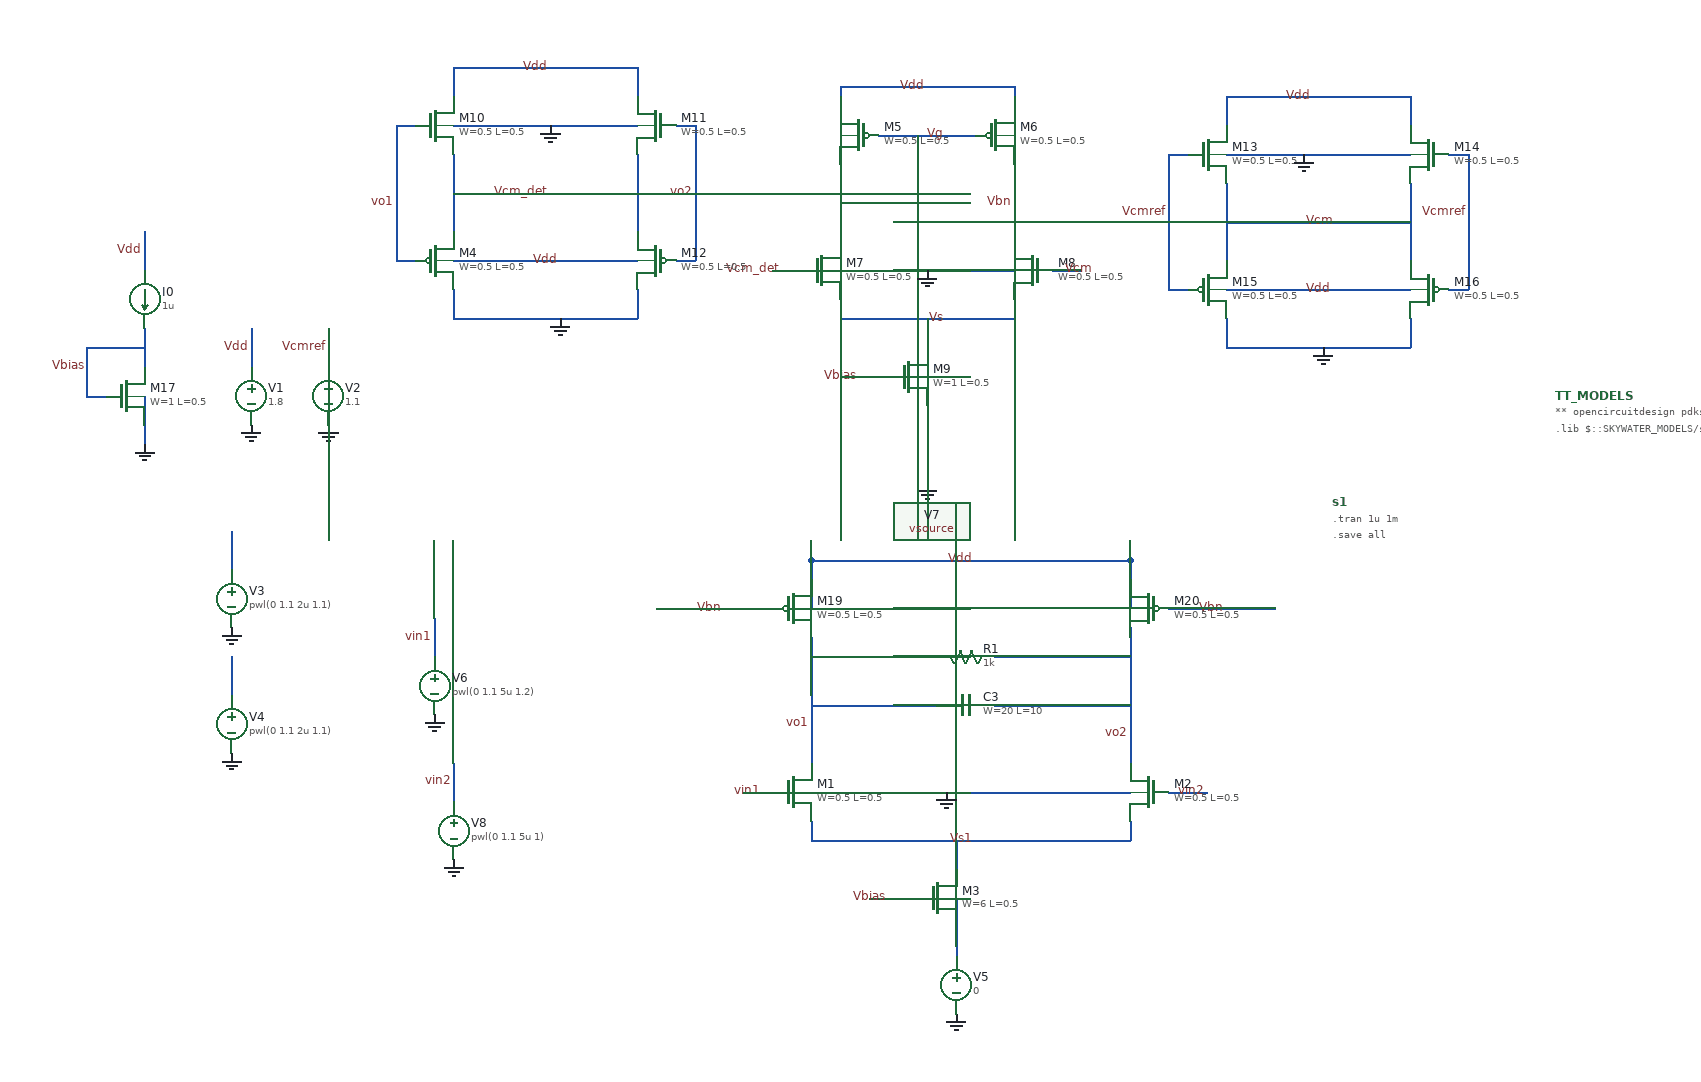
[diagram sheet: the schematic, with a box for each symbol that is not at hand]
v {xschem version=3.4.4 file_version=1.2
}
G {}
K {}
V {}
S {}
E {}
N 440 -20 440 0 {
lab=Vs1}
N 440 0 620 0 {
lab=Vs1}
N 770 -20 770 0 {
lab=Vs1}
N 440 -290 440 -270 {
lab=Vdd}
N 440 -290 620 -290 {
lab=Vdd}
N 770 -290 770 -270 {
lab=Vdd}
N 620 -290 770 -290 {
lab=Vdd}
N 620 0 770 0 {
lab=Vs1}
N 470 -700 470 -620 {
lab=Vg}
N 650 -700 650 -620 {
lab=Vbn}
N 470 -780 470 -760 {
lab=Vdd}
N 470 -780 650 -780 {
lab=Vdd}
N 650 -780 650 -760 {
lab=Vdd}
N 470 -560 470 -540 {
lab=Vs}
N 470 -540 650 -540 {
lab=Vs}
N 650 -560 650 -540 {
lab=Vs}
N 510 -730 610 -730 {
lab=Vg}
N 550 -730 550 -660 {
lab=Vg}
N 470 -660 550 -660 {
lab=Vg}
N 70 -800 70 -770 {
lab=Vdd}
N 70 -800 260 -800 {
lab=Vdd}
N 260 -800 260 -770 {
lab=Vdd}
N 70 -710 70 -630 {
lab=Vcm_det}
N 260 -710 260 -630 {
lab=Vcm_det}
N 70 -570 70 -540 {
lab=GND}
N 70 -540 260 -540 {
lab=GND}
N 260 -570 260 -540 {
lab=GND}
N 10 -740 30 -740 {
lab=vo1}
N 10 -740 10 -600 {
lab=vo1}
N 10 -600 30 -600 {
lab=vo1}
N 300 -740 320 -740 {
lab=vo2}
N 320 -740 320 -600 {
lab=vo2}
N 300 -600 320 -600 {
lab=vo2}
N 870 -770 870 -740 {
lab=Vdd}
N 870 -770 1060 -770 {
lab=Vdd}
N 1060 -770 1060 -740 {
lab=Vdd}
N 870 -680 870 -600 {
lab=Vcm}
N 1060 -680 1060 -600 {
lab=Vcm}
N 870 -540 870 -510 {
lab=GND}
N 870 -510 1060 -510 {
lab=GND}
N 1060 -540 1060 -510 {
lab=GND}
N 810 -710 830 -710 {
lab=Vcmref}
N 810 -710 810 -570 {
lab=Vcmref}
N 810 -570 830 -570 {
lab=Vcmref}
N 1100 -710 1120 -710 {
lab=Vcmref}
N 1120 -710 1120 -570 {
lab=Vcmref}
N 1100 -570 1120 -570 {
lab=Vcmref}
N 560 -540 560 -510 {
lab=Vs}
N 560 -450 560 -420 {
lab=#net1}
N 440 -140 570 -140 {
lab=vo1}
N 630 -140 770 -140 {
lab=vo2}
N -140 -530 -140 -490 {
lab=Vdd}
N 70 -670 260 -670 {
lab=Vcm_det}
N 870 -640 1060 -640 {
lab=Vcm}
N -250 -530 -250 -490 {
lab=Vbias}
N -250 -630 -250 -590 {
lab=Vdd}
N -310 -460 -290 -460 {
lab=Vbias}
N -310 -510 -310 -460 {
lab=Vbias}
N -310 -510 -250 -510 {
lab=Vbias}
N 280 -240 400 -240 {
lab=Vbn}
N 810 -240 920 -240 {
lab=Vbn}
N 400 -590 430 -590 {
lab=Vcm_det}
N 690 -590 720 -590 {
lab=Vcm}
N 370 -50 400 -50 {
lab=vin1}
N 810 -50 850 -50 {
lab=vin2}
N -60 -530 -60 -490 {
lab=Vcmref}
N 470 -480 520 -480 {
lab=Vbias}
N -160 -320 -160 -280 {
lab=#net2}
N -160 -190 -160 -150 {
lab=#net3}
N 440 -150 440 -80 {
lab=vo1}
N 770 -150 770 -80 {
lab=vo2}
N 770 -220 770 -150 {
lab=vo2}
N 70 -740 260 -740 {
lab=GND}
N 70 -600 260 -600 {
lab=Vdd}
N 470 -590 650 -590 {
lab=GND}
N 440 -210 440 -140 {
lab=vo1}
N 870 -710 1060 -710 {
lab=GND}
N 870 -570 1060 -570 {
lab=Vdd}
N 440 -290 440 -240 {
lab=Vdd}
N 770 -290 770 -240 {
lab=Vdd}
N 590 0 590 30 {
lab=Vs1}
N 590 90 590 120 {
lab=#net4}
N 500 60 550 60 {
lab=Vbias}
N 590 60 590 110 {
lab=#net4}
N 440 -50 770 -50 {
lab=GND}
N 560 -480 560 -440 {
lab=#net1}
N 470 -770 470 -730 {
lab=Vdd}
N 650 -770 650 -730 {
lab=Vdd}
N -250 -430 -250 -410 {
lab=GND}
N -250 -460 -250 -420 {
lab=GND}
N 50 -230 50 -190 {
lab=vin1}
N 70 -80 70 -40 {
lab=vin2}
N 440 -190 570 -190 {
lab=vo1}
N 630 -190 770 -190 {
lab=vo2}
C {devices/gnd.sym} 590 180 0 0 {name=l1 lab=GND}
C {devices/gnd.sym} 560 -370 0 0 {name=l2 lab=GND}
C {devices/gnd.sym} 180 -540 0 0 {name=l3 lab=GND}
C {devices/gnd.sym} 970 -510 0 0 {name=l4 lab=GND}
C {devices/vsource.sym} -140 -460 0 0 {name=V1 value=1.8}
C {devices/gnd.sym} -140 -430 0 0 {name=l5 lab=GND}
C {devices/lab_wire.sym} -140 -510 0 0 {name=p1 sig_type=std_logic lab=Vdd
}
C {devices/lab_wire.sym} 610 -290 0 0 {name=p2 sig_type=std_logic lab=Vdd
}
C {devices/lab_wire.sym} 560 -780 0 0 {name=p3 sig_type=std_logic lab=Vdd
}
C {devices/lab_wire.sym} 170 -800 0 0 {name=p4 sig_type=std_logic lab=Vdd
}
C {devices/gnd.sym} -250 -410 0 0 {name=l6 lab=GND}
C {devices/isource.sym} -250 -560 0 0 {name=I0 value=1u}
C {devices/lab_wire.sym} -250 -610 0 0 {name=p6 sig_type=std_logic lab=Vdd
}
C {devices/lab_wire.sym} 390 -50 0 0 {name=p7 sig_type=std_logic lab=vin1

}
C {devices/lab_wire.sym} 850 -50 0 0 {name=p8 sig_type=std_logic lab=vin2


}
C {devices/lab_wire.sym} 440 -120 0 0 {name=p9 sig_type=std_logic lab=vo1

}
C {devices/lab_wire.sym} 770 -110 0 0 {name=p10 sig_type=std_logic lab=vo2


}
C {devices/lab_wire.sym} 10 -660 0 0 {name=p11 sig_type=std_logic lab=vo1

}
C {devices/lab_wire.sym} 320 -670 0 0 {name=p12 sig_type=std_logic lab=vo2


}
C {devices/lab_wire.sym} 170 -670 0 0 {name=p13 sig_type=std_logic lab=Vcm_det



}
C {devices/lab_wire.sym} 950 -640 0 1 {name=p17 sig_type=std_logic lab=Vcm




}
C {devices/lab_wire.sym} 410 -590 0 0 {name=p18 sig_type=std_logic lab=Vcm_det



}
C {devices/lab_wire.sym} 650 -660 0 0 {name=p19 sig_type=std_logic lab=Vbn




}
C {devices/lab_wire.sym} 350 -240 0 0 {name=p20 sig_type=std_logic lab=Vbn




}
C {devices/lab_wire.sym} 870 -240 0 0 {name=p21 sig_type=std_logic lab=Vbn




}
C {devices/vsource.sym} -60 -460 0 0 {name=V2 value=1.1}
C {devices/gnd.sym} -60 -430 0 0 {name=l8 lab=GND}
C {devices/lab_wire.sym} -60 -510 0 0 {name=p22 sig_type=std_logic lab=Vcmref
}
C {devices/lab_wire.sym} -310 -490 0 0 {name=p23 sig_type=std_logic lab=Vbias

}
C {devices/lab_wire.sym} 490 -480 0 0 {name=p24 sig_type=std_logic lab=Vbias

}
C {devices/vsource.sym} -160 -250 0 0 {name=V3 value="pwl(0 1.1 2u 1.1)"}
C {devices/gnd.sym} -160 -220 0 0 {name=l9 lab=GND}
C {devices/vsource.sym} -160 -120 0 0 {name=V4 value="pwl(0 1.1 2u 1.1)"}
C {devices/gnd.sym} -160 -90 0 0 {name=l10 lab=GND}
C {devices/lab_wire.sym} 70 -60 0 0 {name=p26 sig_type=std_logic lab=vin2
}
C {devices/code_shown.sym} 980 -350 0 0 {name=s1 only_toplevel=false 
value=".tran 1u 1m
.save all" }
C {sky130_fd_pr/nfet_01v8.sym} 420 -50 0 0 {name=M1
L=0.5
W=0.5
nf=1 
mult=1
ad="'int((nf+1)/2) * W/nf * 0.29'" 
pd="'2*int((nf+1)/2) * (W/nf + 0.29)'"
as="'int((nf+2)/2) * W/nf * 0.29'" 
ps="'2*int((nf+2)/2) * (W/nf + 0.29)'"
nrd="'0.29 / W'" nrs="'0.29 / W'"
sa=0 sb=0 sd=0
model=nfet_01v8
spiceprefix=X
}
C {sky130_fd_pr/nfet_01v8.sym} 790 -50 0 1 {name=M2
L=0.5
W=0.5
nf=1 
mult=1
ad="'int((nf+1)/2) * W/nf * 0.29'" 
pd="'2*int((nf+1)/2) * (W/nf + 0.29)'"
as="'int((nf+2)/2) * W/nf * 0.29'" 
ps="'2*int((nf+2)/2) * (W/nf + 0.29)'"
nrd="'0.29 / W'" nrs="'0.29 / W'"
sa=0 sb=0 sd=0
model=nfet_01v8
spiceprefix=X
}
C {sky130_fd_pr/pfet_01v8.sym} 50 -600 0 0 {name=M4
L=0.5
W=0.5
nf=1
mult=1
ad="'int((nf+1)/2) * W/nf * 0.29'" 
pd="'2*int((nf+1)/2) * (W/nf + 0.29)'"
as="'int((nf+2)/2) * W/nf * 0.29'" 
ps="'2*int((nf+2)/2) * (W/nf + 0.29)'"
nrd="'0.29 / W'" nrs="'0.29 / W'"
sa=0 sb=0 sd=0
model=pfet_01v8
spiceprefix=X
}
C {sky130_fd_pr/pfet_01v8.sym} 280 -600 0 1 {name=M12
L=0.5
W=0.5
nf=1
mult=1
ad="'int((nf+1)/2) * W/nf * 0.29'" 
pd="'2*int((nf+1)/2) * (W/nf + 0.29)'"
as="'int((nf+2)/2) * W/nf * 0.29'" 
ps="'2*int((nf+2)/2) * (W/nf + 0.29)'"
nrd="'0.29 / W'" nrs="'0.29 / W'"
sa=0 sb=0 sd=0
model=pfet_01v8
spiceprefix=X
}
C {sky130_fd_pr/nfet_01v8.sym} 50 -740 0 0 {name=M10
L=0.5
W=0.5
nf=1 
mult=1
ad="'int((nf+1)/2) * W/nf * 0.29'" 
pd="'2*int((nf+1)/2) * (W/nf + 0.29)'"
as="'int((nf+2)/2) * W/nf * 0.29'" 
ps="'2*int((nf+2)/2) * (W/nf + 0.29)'"
nrd="'0.29 / W'" nrs="'0.29 / W'"
sa=0 sb=0 sd=0
model=nfet_01v8
spiceprefix=X
}
C {sky130_fd_pr/nfet_01v8.sym} 280 -740 0 1 {name=M11
L=0.5
W=0.5
nf=1 
mult=1
ad="'int((nf+1)/2) * W/nf * 0.29'" 
pd="'2*int((nf+1)/2) * (W/nf + 0.29)'"
as="'int((nf+2)/2) * W/nf * 0.29'" 
ps="'2*int((nf+2)/2) * (W/nf + 0.29)'"
nrd="'0.29 / W'" nrs="'0.29 / W'"
sa=0 sb=0 sd=0
model=nfet_01v8
spiceprefix=X
}
C {sky130_fd_pr/pfet_01v8.sym} 490 -730 0 1 {name=M5
L=0.5
W=0.5
nf=1
mult=1
ad="'int((nf+1)/2) * W/nf * 0.29'" 
pd="'2*int((nf+1)/2) * (W/nf + 0.29)'"
as="'int((nf+2)/2) * W/nf * 0.29'" 
ps="'2*int((nf+2)/2) * (W/nf + 0.29)'"
nrd="'0.29 / W'" nrs="'0.29 / W'"
sa=0 sb=0 sd=0
model=pfet_01v8
spiceprefix=X
}
C {sky130_fd_pr/pfet_01v8.sym} 630 -730 0 0 {name=M6
L=0.5
W=0.5
nf=1
mult=1
ad="'int((nf+1)/2) * W/nf * 0.29'" 
pd="'2*int((nf+1)/2) * (W/nf + 0.29)'"
as="'int((nf+2)/2) * W/nf * 0.29'" 
ps="'2*int((nf+2)/2) * (W/nf + 0.29)'"
nrd="'0.29 / W'" nrs="'0.29 / W'"
sa=0 sb=0 sd=0
model=pfet_01v8
spiceprefix=X
}
C {sky130_fd_pr/nfet_01v8.sym} 450 -590 0 0 {name=M7
L=0.5
W=0.5
nf=1 
mult=1
ad="'int((nf+1)/2) * W/nf * 0.29'" 
pd="'2*int((nf+1)/2) * (W/nf + 0.29)'"
as="'int((nf+2)/2) * W/nf * 0.29'" 
ps="'2*int((nf+2)/2) * (W/nf + 0.29)'"
nrd="'0.29 / W'" nrs="'0.29 / W'"
sa=0 sb=0 sd=0
model=nfet_01v8
spiceprefix=X
}
C {sky130_fd_pr/nfet_01v8.sym} 670 -590 0 1 {name=M8
L=0.5
W=0.5
nf=1 
mult=1
ad="'int((nf+1)/2) * W/nf * 0.29'" 
pd="'2*int((nf+1)/2) * (W/nf + 0.29)'"
as="'int((nf+2)/2) * W/nf * 0.29'" 
ps="'2*int((nf+2)/2) * (W/nf + 0.29)'"
nrd="'0.29 / W'" nrs="'0.29 / W'"
sa=0 sb=0 sd=0
model=nfet_01v8
spiceprefix=X
}
C {sky130_fd_pr/nfet_01v8.sym} 540 -480 0 0 {name=M9
L=0.5
W=1
nf=1 
mult=1
ad="'int((nf+1)/2) * W/nf * 0.29'" 
pd="'2*int((nf+1)/2) * (W/nf + 0.29)'"
as="'int((nf+2)/2) * W/nf * 0.29'" 
ps="'2*int((nf+2)/2) * (W/nf + 0.29)'"
nrd="'0.29 / W'" nrs="'0.29 / W'"
sa=0 sb=0 sd=0
model=nfet_01v8
spiceprefix=X
}
C {sky130_fd_pr/nfet_01v8.sym} 850 -710 0 0 {name=M13
L=0.5
W=0.5
nf=1 
mult=1
ad="'int((nf+1)/2) * W/nf * 0.29'" 
pd="'2*int((nf+1)/2) * (W/nf + 0.29)'"
as="'int((nf+2)/2) * W/nf * 0.29'" 
ps="'2*int((nf+2)/2) * (W/nf + 0.29)'"
nrd="'0.29 / W'" nrs="'0.29 / W'"
sa=0 sb=0 sd=0
model=nfet_01v8
spiceprefix=X
}
C {sky130_fd_pr/nfet_01v8.sym} 1080 -710 0 1 {name=M14
L=0.5
W=0.5
nf=1 
mult=1
ad="'int((nf+1)/2) * W/nf * 0.29'" 
pd="'2*int((nf+1)/2) * (W/nf + 0.29)'"
as="'int((nf+2)/2) * W/nf * 0.29'" 
ps="'2*int((nf+2)/2) * (W/nf + 0.29)'"
nrd="'0.29 / W'" nrs="'0.29 / W'"
sa=0 sb=0 sd=0
model=nfet_01v8
spiceprefix=X
}
C {sky130_fd_pr/pfet_01v8.sym} 850 -570 0 0 {name=M15
L=0.5
W=0.5
nf=1
mult=1
ad="'int((nf+1)/2) * W/nf * 0.29'" 
pd="'2*int((nf+1)/2) * (W/nf + 0.29)'"
as="'int((nf+2)/2) * W/nf * 0.29'" 
ps="'2*int((nf+2)/2) * (W/nf + 0.29)'"
nrd="'0.29 / W'" nrs="'0.29 / W'"
sa=0 sb=0 sd=0
model=pfet_01v8
spiceprefix=X
}
C {sky130_fd_pr/pfet_01v8.sym} 1080 -570 0 1 {name=M16
L=0.5
W=0.5
nf=1
mult=1
ad="'int((nf+1)/2) * W/nf * 0.29'" 
pd="'2*int((nf+1)/2) * (W/nf + 0.29)'"
as="'int((nf+2)/2) * W/nf * 0.29'" 
ps="'2*int((nf+2)/2) * (W/nf + 0.29)'"
nrd="'0.29 / W'" nrs="'0.29 / W'"
sa=0 sb=0 sd=0
model=pfet_01v8
spiceprefix=X
}
C {sky130_fd_pr/nfet_01v8.sym} -270 -460 0 0 {name=M17
L=0.5
W=1
nf=1 
mult=1
ad="'int((nf+1)/2) * W/nf * 0.29'" 
pd="'2*int((nf+1)/2) * (W/nf + 0.29)'"
as="'int((nf+2)/2) * W/nf * 0.29'" 
ps="'2*int((nf+2)/2) * (W/nf + 0.29)'"
nrd="'0.29 / W'" nrs="'0.29 / W'"
sa=0 sb=0 sd=0
model=nfet_01v8
spiceprefix=X
}
C {sky130_fd_pr/cap_mim_m3_1.sym} 600 -140 1 0 {name=C3 model=cap_mim_m3_1 W=20 L=10 MF=1 spiceprefix=X}
C {devices/code.sym} 1210 -460 0 0 {name=TT_MODELS
only_toplevel=true
format="tcleval( @value )"
value="
** opencircuitdesign pdks install
.lib $::SKYWATER_MODELS/sky130.lib.spice tt

"
spice_ignore=false}
C {devices/vsource.sym} 560 -400 0 0 {name=V7 value=0}
C {devices/lab_wire.sym} 580 -540 0 0 {name=p29 sig_type=std_logic lab=Vs

}
C {devices/lab_wire.sym} 700 -590 0 1 {name=p16 sig_type=std_logic lab=Vcm




}
C {devices/vsource.sym} 590 150 0 0 {name=V5 value=0}
C {devices/lab_wire.sym} 580 -730 0 0 {name=p27 sig_type=std_logic lab=Vg




}
C {devices/lab_wire.sym} 50 -210 0 0 {name=p28 sig_type=std_logic lab=vin1
}
C {devices/gnd.sym} 170 -740 0 0 {name=l12 lab=GND}
C {devices/gnd.sym} 950 -710 0 0 {name=l13 lab=GND}
C {devices/lab_wire.sym} 180 -600 0 0 {name=p25 sig_type=std_logic lab=Vdd
}
C {devices/lab_wire.sym} 980 -570 0 0 {name=p30 sig_type=std_logic lab=Vdd
}
C {devices/gnd.sym} 560 -590 0 0 {name=l14 lab=GND}
C {devices/lab_wire.sym} 960 -770 0 0 {name=p5 sig_type=std_logic lab=Vdd
}
C {devices/lab_wire.sym} 810 -650 0 0 {name=p14 sig_type=std_logic lab=Vcmref
}
C {devices/lab_wire.sym} 1120 -650 0 0 {name=p15 sig_type=std_logic lab=Vcmref
}
C {sky130_fd_pr/pfet_01v8_lvt.sym} 420 -240 0 0 {name=M19
L=0.5
W=0.5
nf=1
mult=1
ad="'int((nf+1)/2) * W/nf * 0.29'" 
pd="'2*int((nf+1)/2) * (W/nf + 0.29)'"
as="'int((nf+2)/2) * W/nf * 0.29'" 
ps="'2*int((nf+2)/2) * (W/nf + 0.29)'"
nrd="'0.29 / W'" nrs="'0.29 / W'"
sa=0 sb=0 sd=0
model=pfet_01v8_lvt
spiceprefix=X
}
C {sky130_fd_pr/pfet_01v8_lvt.sym} 790 -240 0 1 {name=M20
L=0.5
W=0.5
nf=1
mult=1
ad="'int((nf+1)/2) * W/nf * 0.29'" 
pd="'2*int((nf+1)/2) * (W/nf + 0.29)'"
as="'int((nf+2)/2) * W/nf * 0.29'" 
ps="'2*int((nf+2)/2) * (W/nf + 0.29)'"
nrd="'0.29 / W'" nrs="'0.29 / W'"
sa=0 sb=0 sd=0
model=pfet_01v8_lvt
spiceprefix=X
}
C {devices/lab_wire.sym} 520 60 0 0 {name=p31 sig_type=std_logic lab=Vbias

}
C {sky130_fd_pr/nfet_01v8.sym} 570 60 0 0 {name=M3
L=0.5
W=6
nf=1 
mult=1
ad="'int((nf+1)/2) * W/nf * 0.29'" 
pd="'2*int((nf+1)/2) * (W/nf + 0.29)'"
as="'int((nf+2)/2) * W/nf * 0.29'" 
ps="'2*int((nf+2)/2) * (W/nf + 0.29)'"
nrd="'0.29 / W'" nrs="'0.29 / W'"
sa=0 sb=0 sd=0
model=nfet_01v8
spiceprefix=X
}
C {devices/lab_wire.sym} 610 0 0 0 {name=p32 sig_type=std_logic lab=Vs1

}
C {devices/gnd.sym} 580 -50 0 0 {name=l7 lab=GND}
C {devices/vsource.sym} 50 -160 0 0 {name=V6 value="pwl(0 1.1 5u 1.2)"}
C {devices/gnd.sym} 50 -130 0 0 {name=l11 lab=GND}
C {devices/vsource.sym} 70 -10 0 0 {name=V8 value="pwl(0 1.1 5u 1)"}
C {devices/gnd.sym} 70 20 0 0 {name=l15 lab=GND}
C {devices/res.sym} 600 -190 1 0 {name=R1
value=1k
footprint=1206
device=resistor
m=1}
